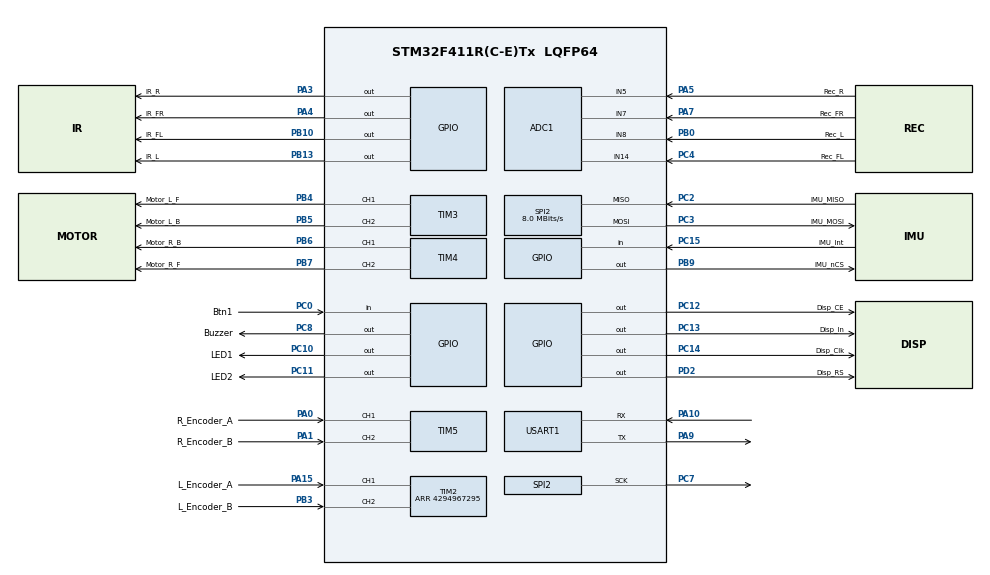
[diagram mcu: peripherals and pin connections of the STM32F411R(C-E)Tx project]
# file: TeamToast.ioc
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ADC1.Channel-0\#ChannelRegularConversion=ADC_CHANNEL_8
ADC1.NbrOfConversionFlag=1
ADC1.Rank-0\#ChannelRegularConversion=1
ADC1.SamplingTime-0\#ChannelRegularConversion=ADC_SAMPLETIME_3CYCLES
ADC1.master=1
Mcu.Family=STM32F4
Mcu.Name=STM32F411R(C-E)Tx
Mcu.Package=LQFP64
NVIC.PriorityGroup=NVIC_PRIORITYGROUP_4
PA0-WKUP.GPIO_Label=R_Encoder_A
PA0-WKUP.GPIO_PuPd=GPIO_PULLUP
PA0-WKUP.Signal=S_TIM5_CH1
PA1.GPIO_Label=R_Encoder_B
PA1.GPIO_PuPd=GPIO_PULLUP
PA1.Signal=S_TIM5_CH2
PA10.Mode=Asynchronous
PA10.Signal=USART1_RX
PA13.Mode=Serial_Wire
PA13.Signal=SYS_JTMS-SWDIO
PA14.Mode=Serial_Wire
PA14.Signal=SYS_JTCK-SWCLK
PA15.GPIO_Label=L_Encoder_A
PA15.GPIO_PuPd=GPIO_PULLUP
PA15.Signal=S_TIM2_CH1_ETR
PA3.GPIO_Label=IR_R
PA3.Signal=GPIO_Output
PA4.GPIO_Label=IR_FR
PA4.Signal=GPIO_Output
PA5.GPIO_Label=Rec_R
PA5.Signal=ADCx_IN5
PA7.GPIO_Label=Rec_FR
PA7.Signal=ADCx_IN7
PA9.Mode=Asynchronous
PA9.Signal=USART1_TX
PB0.GPIO_Label=Rec_L
PB0.Signal=ADCx_IN8
PB10.GPIO_Label=IR_FL
PB10.Signal=GPIO_Output
PB13.GPIO_Label=IR_L
PB13.Signal=GPIO_Output
PB3.GPIO_Label=L_Encoder_B
PB3.GPIO_PuPd=GPIO_PULLUP
PB3.Signal=S_TIM2_CH2
PB4.GPIO_Label=Motor_L_F
PB4.Signal=S_TIM3_CH1
PB5.GPIO_Label=Motor_L_B
PB5.Signal=S_TIM3_CH2
PB6.GPIO_Label=Motor_R_B
PB6.Signal=S_TIM4_CH1
PB7.GPIO_Label=Motor_R_F
PB7.Signal=S_TIM4_CH2
PB9.GPIO_Label=IMU_nCS
PB9.Signal=GPIO_Output
PC0.GPIO_Label=Btn1
PC0.Signal=GPIO_Input
PC10.GPIO_Label=LED1
PC10.Signal=GPIO_Output
PC11.GPIO_Label=LED2
PC11.Signal=GPIO_Output
PC12.GPIO_Label=Disp_CE
PC12.Signal=GPIO_Output
PC13-ANTI_TAMP.GPIO_Label=Disp_In
PC13-ANTI_TAMP.Signal=GPIO_Output
PC14-OSC32_IN.GPIO_Label=Disp_Clk
PC14-OSC32_IN.Signal=GPIO_Output
PC15-OSC32_OUT.GPIO_Label=IMU_Int
PC15-OSC32_OUT.Signal=GPIO_Input
PC2.GPIO_Label=IMU_MISO
PC2.Mode=Full_Duplex_Master
PC2.Signal=SPI2_MISO
PC3.GPIO_Label=IMU_MOSI
PC3.Mode=Full_Duplex_Master
PC3.Signal=SPI2_MOSI
PC4.GPIO_Label=Rec_FL
PC4.Signal=ADCx_IN14
PC7.Mode=Full_Duplex_Master
PC7.Signal=SPI2_SCK
PC8.GPIO_Label=Buzzer
PC8.Signal=GPIO_Output
PD2.GPIO_Label=Disp_RS
PD2.Signal=GPIO_Output
ProjectManager.HeapSize=0x200
ProjectManager.StackSize=0x400
ProjectManager.TargetToolchain=SW4STM32
RCC.48MHZClocksFreq_Value=50000000
RCC.AHBFreq_Value=16000000
RCC.APB1Freq_Value=16000000
RCC.APB1TimFreq_Value=16000000
RCC.APB2Freq_Value=16000000
RCC.APB2TimFreq_Value=16000000
RCC.CortexFreq_Value=16000000
RCC.HCLKFreq_Value=16000000
RCC.HSE_VALUE=25000000
RCC.HSI_VALUE=16000000
RCC.LSE_VALUE=32768
RCC.PLLM=8
RCC.PLLN=100
RCC.SYSCLKFreq_VALUE=16000000
RCC.VCOOutputFreq_Value=200000000
SH.ADCx_IN14.0=ADC1_IN14,IN14
SH.ADCx_IN5.0=ADC1_IN5,IN5
SH.ADCx_IN7.0=ADC1_IN7,IN7
SH.ADCx_IN8.0=ADC1_IN8,IN8
SH.S_TIM2_CH1_ETR.0=TIM2_CH1,Encoder_Interface
SH.S_TIM2_CH2.0=TIM2_CH2,Encoder_Interface
SH.S_TIM3_CH1.0=TIM3_CH1,PWM Generation1 CH1
SH.S_TIM3_CH2.0=TIM3_CH2,PWM Generation2 CH2
SH.S_TIM4_CH1.0=TIM4_CH1,PWM Generation1 CH1
SH.S_TIM4_CH2.0=TIM4_CH2,PWM Generation2 CH2
SH.S_TIM5_CH1.0=TIM5_CH1,Encoder_Interface
SH.S_TIM5_CH2.0=TIM5_CH2,Encoder_Interface
SPI2.BaudRatePrescaler=SPI_BAUDRATEPRESCALER_2
SPI2.CalculateBaudRate=8.0 MBits/s
SPI2.Direction=SPI_DIRECTION_2LINES
SPI2.Mode=SPI_MODE_MASTER
SPI2.VirtualType=VM_MASTER
TIM2.EncoderMode=TIM_ENCODERMODE_TI12
TIM2.IC1Filter=10
TIM2.IC2Filter=10
TIM2.Period=4294967295
TIM3.Channel-PWM\ Generation1\ CH1=TIM_CHANNEL_1
TIM3.Channel-PWM\ Generation2\ CH2=TIM_CHANNEL_2
TIM4.Channel-PWM\ Generation1\ CH1=TIM_CHANNEL_1
TIM4.Channel-PWM\ Generation2\ CH2=TIM_CHANNEL_2
USART1.VirtualMode=VM_ASYNC
board=custom

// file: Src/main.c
/**
  ******************************************************************************
  * @file           : main.c
  * @brief          : Main program body
  ******************************************************************************
  ** This notice applies to any and all portions of this file
  * that are not between comment pairs USER CODE BEGIN and
  * USER CODE END. Other portions of this file, whether
  * inserted by the user or by software development tools
  * are owned by their respective copyright owners.
  *
  * COPYRIGHT(c) 2019 STMicroelectronics
  *
  * Redistribution and use in source and binary forms, with or without modification,
  * are permitted provided that the following conditions are met:
  *   1. Redistributions of source code must retain the above copyright notice,
  *      this list of conditions and the following disclaimer.
  *   2. Redistributions in binary form must reproduce the above copyright notice,
  *      this list of conditions and the following disclaimer in the documentation
  *      and/or other materials provided with the distribution.
  *   3. Neither the name of STMicroelectronics nor the names of its contributors
  *      may be used to endorse or promote products derived from this software
  *      without specific prior written permission.
  *
  * THIS SOFTWARE IS PROVIDED BY THE COPYRIGHT HOLDERS AND CONTRIBUTORS "AS IS"
  * AND ANY EXPRESS OR IMPLIED WARRANTIES, INCLUDING, BUT NOT LIMITED TO, THE
  * IMPLIED WARRANTIES OF MERCHANTABILITY AND FITNESS FOR A PARTICULAR PURPOSE ARE
  * DISCLAIMED. IN NO EVENT SHALL THE COPYRIGHT HOLDER OR CONTRIBUTORS BE LIABLE
  * FOR ANY DIRECT, INDIRECT, INCIDENTAL, SPECIAL, EXEMPLARY, OR CONSEQUENTIAL
  * DAMAGES (INCLUDING, BUT NOT LIMITED TO, PROCUREMENT OF SUBSTITUTE GOODS OR
  * SERVICES; LOSS OF USE, DATA, OR PROFITS; OR BUSINESS INTERRUPTION) HOWEVER
  * CAUSED AND ON ANY THEORY OF LIABILITY, WHETHER IN CONTRACT, STRICT LIABILITY,
  * OR TORT (INCLUDING NEGLIGENCE OR OTHERWISE) ARISING IN ANY WAY OUT OF THE USE
  * OF THIS SOFTWARE, EVEN IF ADVISED OF THE POSSIBILITY OF SUCH DAMAGE.
  *
  ******************************************************************************
  */
#include "main.h"
#include "stm32f4xx_hal.h"
#include "adc.h"
#include "spi.h"
#include "tim.h"
#include "usart.h"
#include "gpio.h"

/* USER CODE BEGIN Includes */
#define SWO_DEBUG_ENABLED 0
/* USER CODE END Includes */

/* USER CODE BEGIN PV */
/* Private variables ---------------------------------------------------------*/

/* USER CODE END PV */

void SystemClock_Config(void);

/* USER CODE BEGIN PFP */
/* Private function prototypes -----------------------------------------------*/

/* USER CODE END PFP */

int main(void)
{

  /* MCU Configuration----------------------------------------------------------*/

  /* Reset of all peripherals, Initializes the Flash interface and the Systick. */
  HAL_Init();

  /* Configure the system clock */
  SystemClock_Config();

  /* Initialize all configured peripherals */
  MX_GPIO_Init();
  MX_ADC1_Init();
  MX_SPI2_Init();
  MX_USART1_UART_Init();
  MX_TIM4_Init();
  MX_TIM3_Init();
  MX_TIM5_Init();
  MX_TIM2_Init();
  /* USER CODE BEGIN 2 */

  //Undocumented stuff, needed to start encoder
  HAL_TIM_Encoder_Start(&htim2, TIM_CHANNEL_1 | TIM_CHANNEL_2);
  TIM2->EGR=TIM_EGR_UG;
  TIM2->CR1=TIM_CR1_CEN;

  //Undocumented stuff, needed to start encoder
  HAL_TIM_Encoder_Start(&htim5,  TIM_CHANNEL_1 | TIM_CHANNEL_2);
  TIM5->EGR=TIM_EGR_UG;
  TIM5->CR1=TIM_CR1_CEN;

  HAL_TIM_Base_Start(&htim3);

  HAL_TIM_Base_Start(&htim4);

  uint8_t buf[2];
  buf[0] = 0x6A; //User control reg
  buf[1] = 0x10; //I2c disable bit

  HAL_GPIO_WritePin(IMU_nCS_GPIO_Port, IMU_nCS_Pin, GPIO_PIN_RESET);
  HAL_SPI_Transmit(&hspi2, buf, sizeof(buf), 100);
  HAL_GPIO_WritePin(IMU_nCS_GPIO_Port, IMU_nCS_Pin, GPIO_PIN_SET);
  HAL_Delay(10);

  buf[0] = 0x6B; //power mgmt register
  buf[1] = 0x80; //reset
  HAL_GPIO_WritePin(IMU_nCS_GPIO_Port, IMU_nCS_Pin, GPIO_PIN_RESET);
  HAL_SPI_Transmit(&hspi2, buf, sizeof(buf), 100);
  HAL_GPIO_WritePin(IMU_nCS_GPIO_Port, IMU_nCS_Pin, GPIO_PIN_SET);
  HAL_Delay(10);

  buf[0] = 0x68; //signal path
  buf[1] = 0x07; //reset
  HAL_GPIO_WritePin(IMU_nCS_GPIO_Port, IMU_nCS_Pin, GPIO_PIN_RESET);
  HAL_SPI_Transmit(&hspi2, buf, sizeof(buf), 100);
  HAL_GPIO_WritePin(IMU_nCS_GPIO_Port, IMU_nCS_Pin, GPIO_PIN_SET);
  HAL_Delay(10);

  buf[0] = 0x6B; //signal path
  buf[1] = 0x03; //gyro pll select
  HAL_GPIO_WritePin(IMU_nCS_GPIO_Port, IMU_nCS_Pin, GPIO_PIN_RESET);
  HAL_SPI_Transmit(&hspi2, buf, sizeof(buf), 100);
  HAL_GPIO_WritePin(IMU_nCS_GPIO_Port, IMU_nCS_Pin, GPIO_PIN_SET);
  HAL_Delay(10);

  //IMU -> read WHOAMI reg
  uint8_t addr, data;
  addr = 0x75 | 0x80; // WHOAMI | read flag
  data = 0;
  HAL_GPIO_WritePin(IMU_nCS_GPIO_Port, IMU_nCS_Pin, GPIO_PIN_RESET);
  HAL_SPI_Transmit(&hspi2, &addr, sizeof(addr), 100);
  HAL_SPI_Receive(&hspi2, &data, sizeof(data), 100);
  HAL_GPIO_WritePin(IMU_nCS_GPIO_Port, IMU_nCS_Pin, GPIO_PIN_SET);
  HAL_Delay(10);
  if(data != 0x70)
  {
    char printbuf[32] = "ERROR";
    //sprintf(printbuf, "WHOAMI: %hd\r\n", data);
    print((uint8_t*)printbuf);
  }

  //Notes:
  /*
  Registers 19 to 24 – Gyro Offset Registers
  25 -> sample rate divider
  26-> config
  */
  //Configuration
  //set sample rate to 1khz
  buf[0] = 0x19; //Sample rate divider
  buf[1] = 0x00; //1KHz
  HAL_GPIO_WritePin(IMU_nCS_GPIO_Port, IMU_nCS_Pin, GPIO_PIN_RESET);
  HAL_SPI_Transmit(&hspi2, buf, sizeof(buf), 100);
  HAL_GPIO_WritePin(IMU_nCS_GPIO_Port, IMU_nCS_Pin, GPIO_PIN_SET);
  HAL_Delay(10);

  //setup dlpf
  buf[0] = 0x1A; //Config
  buf[1] = 0x01; //DLPF -> 184Hz
  HAL_GPIO_WritePin(IMU_nCS_GPIO_Port, IMU_nCS_Pin, GPIO_PIN_RESET);
  HAL_SPI_Transmit(&hspi2, buf, sizeof(buf), 100);
  HAL_GPIO_WritePin(IMU_nCS_GPIO_Port, IMU_nCS_Pin, GPIO_PIN_SET);
  HAL_Delay(10);

  //set scale
  buf[0] = 0x1A; //Gyro Config
  buf[1] = 0x18; //FS -> 2000dps
  HAL_GPIO_WritePin(IMU_nCS_GPIO_Port, IMU_nCS_Pin, GPIO_PIN_RESET);
  HAL_SPI_Transmit(&hspi2, buf, sizeof(buf), 100);
  HAL_GPIO_WritePin(IMU_nCS_GPIO_Port, IMU_nCS_Pin, GPIO_PIN_SET);
  HAL_Delay(10);

  /* USER CODE END 2 */

  /* Infinite loop */
  /* USER CODE BEGIN WHILE */

  while (1)
  {
    HAL_GPIO_TogglePin(GPIOC, GPIO_PIN_10);

    setPWM(htim3, TIM_CHANNEL_1, 255, 127);
    setPWM(htim4, TIM_CHANNEL_1, 255, 127);

    // char buf[16];
    // sprintf(buf, "2:%d, 5:%d\r\n", TIM2->CNT, TIM5->CNT);

    // print((uint8_t*)buf);

    uint8_t addrH = 0x47 | 0x80; // Gyro Z high byte | read flag
    uint8_t addrL = 0x48 | 0x80; // Gyro Z high byte | read flag
    int16_t gzData;
    uint8_t dataH, dataL;
    HAL_GPIO_WritePin(IMU_nCS_GPIO_Port, IMU_nCS_Pin, GPIO_PIN_RESET);
    HAL_SPI_Transmit(&hspi2, &addrH, sizeof(addrH), 100);
    HAL_SPI_Receive(&hspi2, &dataH, sizeof(dataH), 100);
    HAL_SPI_Transmit(&hspi2, &addrL, sizeof(addrL), 100);
    HAL_SPI_Receive(&hspi2, &dataL, sizeof(dataL), 100);
    HAL_GPIO_WritePin(IMU_nCS_GPIO_Port, IMU_nCS_Pin, GPIO_PIN_SET);
    HAL_Delay(10);

    gzData = ((int16_t)dataH) << 8 | ((int16_t)dataL);
    char gzbuf[64];
    sprintf(gzbuf, "GyroZ: %d, %d, %hd\r\n", dataH, dataL, gzData);
    print((uint8_t*)gzbuf);
    HAL_Delay(100);
  /* USER CODE END WHILE */

  }

}

void SystemClock_Config(void)
{

  RCC_OscInitTypeDef RCC_OscInitStruct;
  RCC_ClkInitTypeDef RCC_ClkInitStruct;

    /**Configure the main internal regulator output voltage
    */
  __HAL_RCC_PWR_CLK_ENABLE();

  __HAL_PWR_VOLTAGESCALING_CONFIG(PWR_REGULATOR_VOLTAGE_SCALE1);

    /**Initializes the CPU, AHB and APB busses clocks
    */
  RCC_OscInitStruct.OscillatorType = RCC_OSCILLATORTYPE_HSI;
  RCC_OscInitStruct.HSIState = RCC_HSI_ON;
  RCC_OscInitStruct.HSICalibrationValue = 16;
  RCC_OscInitStruct.PLL.PLLState = RCC_PLL_ON;
  RCC_OscInitStruct.PLL.PLLSource = RCC_PLLSOURCE_HSI;
  RCC_OscInitStruct.PLL.PLLM = 8;
  RCC_OscInitStruct.PLL.PLLN = 100;
  RCC_OscInitStruct.PLL.PLLP = RCC_PLLP_DIV2;
  RCC_OscInitStruct.PLL.PLLQ = 4;
  if (HAL_RCC_OscConfig(&RCC_OscInitStruct) != HAL_OK)
  {
    _Error_Handler(__FILE__, __LINE__);
  }

    /**Initializes the CPU, AHB and APB busses clocks
    */
  RCC_ClkInitStruct.ClockType = RCC_CLOCKTYPE_HCLK|RCC_CLOCKTYPE_SYSCLK
                              |RCC_CLOCKTYPE_PCLK1|RCC_CLOCKTYPE_PCLK2;
  RCC_ClkInitStruct.SYSCLKSource = RCC_SYSCLKSOURCE_PLLCLK;
  RCC_ClkInitStruct.AHBCLKDivider = RCC_SYSCLK_DIV1;
  RCC_ClkInitStruct.APB1CLKDivider = RCC_HCLK_DIV2;
  RCC_ClkInitStruct.APB2CLKDivider = RCC_HCLK_DIV1;

  if (HAL_RCC_ClockConfig(&RCC_ClkInitStruct, FLASH_LATENCY_3) != HAL_OK)
  {
    _Error_Handler(__FILE__, __LINE__);
  }

    /**Configure the Systick interrupt time
    */
  HAL_SYSTICK_Config(HAL_RCC_GetHCLKFreq()/1000);

    /**Configure the Systick
    */
  HAL_SYSTICK_CLKSourceConfig(SYSTICK_CLKSOURCE_HCLK);

  /* SysTick_IRQn interrupt configuration */
  HAL_NVIC_SetPriority(SysTick_IRQn, 0, 0);
}

void _Error_Handler(char *file, int line)
{
  while(1)
  {
  }
}

/************************ (C) COPYRIGHT STMicroelectronics *****END OF FILE****/
